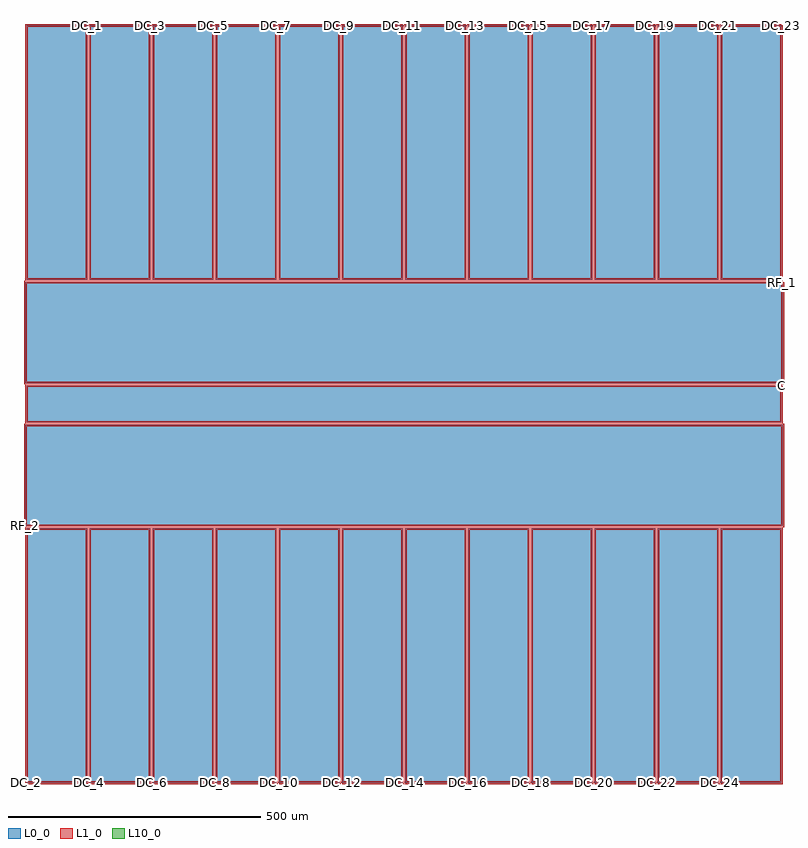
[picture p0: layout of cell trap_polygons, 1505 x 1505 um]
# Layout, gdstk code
import gdstk
lib = gdstk.Library(unit=1e-6, precision=1e-09)
def P(c, l, *ps):  # polygons
    for p in ps: c.add(gdstk.Polygon(p, *l))
L0_0 = (0, 0)
L1_0 = (1, 0)
L10_0 = (10, 0)

trap_polygons = lib.new_cell('trap_polygons')
P(trap_polygons, L0_0, [(627.5,-750),(627.5,-246.5),(747.5,-246.5),(747.5,-750),(627.5,-750)],
  [(747.5,750),(747.5,246.5),(627.5,246.5),(627.5,750),(747.5,750)],
  [(502.5,-750),(502.5,-246.5),(622.5,-246.5),(622.5,-750),(502.5,-750)],
  [(622.5,750),(622.5,246.5),(502.5,246.5),(502.5,750),(622.5,750)],
  [(377.5,-750),(377.5,-246.5),(497.5,-246.5),(497.5,-750),(377.5,-750)],
  [(497.5,750),(497.5,246.5),(377.5,246.5),(377.5,750),(497.5,750)],
  [(252.5,-750),(252.5,-246.5),(372.5,-246.5),(372.5,-750),(252.5,-750)],
  [(372.5,750),(372.5,246.5),(252.5,246.5),(252.5,750),(372.5,750)],
  [(127.5,-750),(127.5,-246.5),(247.5,-246.5),(247.5,-750),(127.5,-750)],
  [(247.5,750),(247.5,246.5),(127.5,246.5),(127.5,750),(247.5,750)],
  [(2.5,-750),(2.5,-246.5),(122.5,-246.5),(122.5,-750),(2.5,-750)],
  [(122.5,750),(122.5,246.5),(2.5,246.5),(2.5,750),(122.5,750)],
  [(-122.5,-750),(-122.5,-246.5),(-2.5,-246.5),(-2.5,-750),(-122.5,-750)],
  [(-2.5,750),(-2.5,246.5),(-122.5,246.5),(-122.5,750),(-2.5,750)],
  [(-247.5,-750),(-247.5,-246.5),(-127.5,-246.5),(-127.5,-750),(-247.5,-750)],
  [(-127.5,750),(-127.5,246.5),(-247.5,246.5),(-247.5,750),(-127.5,750)],
  [(-372.5,-750),(-372.5,-246.5),(-252.5,-246.5),(-252.5,-750),(-372.5,-750)],
  [(-252.5,750),(-252.5,246.5),(-372.5,246.5),(-372.5,750),(-252.5,750)],
  [(-497.5,-750),(-497.5,-246.5),(-377.5,-246.5),(-377.5,-750),(-497.5,-750)],
  [(-377.5,750),(-377.5,246.5),(-497.5,246.5),(-497.5,750),(-377.5,750)],
  [(-622.5,-750),(-622.5,-246.5),(-502.5,-246.5),(-502.5,-750),(-622.5,-750)],
  [(-502.5,750),(-502.5,246.5),(-622.5,246.5),(-622.5,750),(-502.5,750)],
  [(-747.5,-750),(-747.5,-246.5),(-627.5,-246.5),(-627.5,-750),(-747.5,-750)],
  [(-627.5,750),(-627.5,246.5),(-747.5,246.5),(-747.5,750),(-627.5,750)],
  [(747.5,36.5),(747.5,-36.5),(-747.5,-36.5),(-747.5,36.5),(747.5,36.5)],
  [(-750,-241.5),(-750,-41.5),(750,-41.5),(750,-241.5),(-750,-241.5)],
  [(750,241.5),(750,41.5),(-750,41.5),(-750,241.5),(750,241.5)])
P(trap_polygons, L1_0, [(625,-750),(630,-750),(630,-249),(745,-249),(745,-747.5),(627.5,-747.5),(627.5,-752.5),(750,-752.5),(750,-244),(625,-244)],
  [(750,750),(745,750),(745,249),(630,249),(630,747.5),(747.5,747.5),(747.5,752.5),(625,752.5),(625,244),(750,244)],
  [(500,-750),(505,-750),(505,-249),(620,-249),(620,-747.5),(502.5,-747.5),(502.5,-752.5),(625,-752.5),(625,-244),(500,-244)],
  [(625,750),(620,750),(620,249),(505,249),(505,747.5),(622.5,747.5),(622.5,752.5),(500,752.5),(500,244),(625,244)],
  [(375,-750),(380,-750),(380,-249),(495,-249),(495,-747.5),(377.5,-747.5),(377.5,-752.5),(500,-752.5),(500,-244),(375,-244)],
  [(500,750),(495,750),(495,249),(380,249),(380,747.5),(497.5,747.5),(497.5,752.5),(375,752.5),(375,244),(500,244)],
  [(250,-750),(255,-750),(255,-249),(370,-249),(370,-747.5),(252.5,-747.5),(252.5,-752.5),(375,-752.5),(375,-244),(250,-244)],
  [(375,750),(370,750),(370,249),(255,249),(255,747.5),(372.5,747.5),(372.5,752.5),(250,752.5),(250,244),(375,244)],
  [(125,-750),(130,-750),(130,-249),(245,-249),(245,-747.5),(127.5,-747.5),(127.5,-752.5),(250,-752.5),(250,-244),(125,-244)],
  [(250,750),(245,750),(245,249),(130,249),(130,747.5),(247.5,747.5),(247.5,752.5),(125,752.5),(125,244),(250,244)],
  [(0,-750),(5,-750),(5,-249),(120,-249),(120,-747.5),(2.5,-747.5),(2.5,-752.5),(125,-752.5),(125,-244),(0,-244)],
  [(125,750),(120,750),(120,249),(5,249),(5,747.5),(122.5,747.5),(122.5,752.5),(0,752.5),(0,244),(125,244)],
  [(-125,-750),(-120,-750),(-120,-249),(-5,-249),(-5,-747.5),(-122.5,-747.5),(-122.5,-752.5),(0,-752.5),(0,-244),(-125,-244)],
  [(0,750),(-5,750),(-5,249),(-120,249),(-120,747.5),(-2.5,747.5),(-2.5,752.5),(-125,752.5),(-125,244),(0,244)],
  [(-250,-750),(-245,-750),(-245,-249),(-130,-249),(-130,-747.5),(-247.5,-747.5),(-247.5,-752.5),(-125,-752.5),(-125,-244),(-250,-244)],
  [(-125,750),(-130,750),(-130,249),(-245,249),(-245,747.5),(-127.5,747.5),(-127.5,752.5),(-250,752.5),(-250,244),(-125,244)],
  [(-375,-750),(-370,-750),(-370,-249),(-255,-249),(-255,-747.5),(-372.5,-747.5),(-372.5,-752.5),(-250,-752.5),(-250,-244),(-375,-244)],
  [(-250,750),(-255,750),(-255,249),(-370,249),(-370,747.5),(-252.5,747.5),(-252.5,752.5),(-375,752.5),(-375,244),(-250,244)],
  [(-500,-750),(-495,-750),(-495,-249),(-380,-249),(-380,-747.5),(-497.5,-747.5),(-497.5,-752.5),(-375,-752.5),(-375,-244),(-500,-244)],
  [(-375,750),(-380,750),(-380,249),(-495,249),(-495,747.5),(-377.5,747.5),(-377.5,752.5),(-500,752.5),(-500,244),(-375,244)],
  [(-625,-750),(-620,-750),(-620,-249),(-505,-249),(-505,-747.5),(-622.5,-747.5),(-622.5,-752.5),(-500,-752.5),(-500,-244),(-625,-244)],
  [(-500,750),(-505,750),(-505,249),(-620,249),(-620,747.5),(-502.5,747.5),(-502.5,752.5),(-625,752.5),(-625,244),(-500,244)],
  [(-750,-750),(-745,-750),(-745,-249),(-630,-249),(-630,-747.5),(-747.5,-747.5),(-747.5,-752.5),(-625,-752.5),(-625,-244),(-750,-244)],
  [(-625,750),(-630,750),(-630,249),(-745,249),(-745,747.5),(-627.5,747.5),(-627.5,752.5),(-750,752.5),(-750,244),(-625,244)],
  [(750,36.5),(745,36.5),(745,-34),(-745,-34),(-745,34),(747.5,34),(747.5,39),(-750,39),(-750,-39),(750,-39)],
  [(-752.5,-241.5),(-747.5,-241.5),(-747.5,-44),(747.5,-44),(747.5,-239),(-750,-239),(-750,-244),(752.5,-244),(752.5,-39),(-752.5,-39)],
  [(752.5,241.5),(747.5,241.5),(747.5,44),(-747.5,44),(-747.5,239),(750,239),(750,244),(-752.5,244),(-752.5,39),(752.5,39)])
P(trap_polygons, L10_0, [(0,0),(0,0),(0,0),(0,0)])
trap_polygons.add(gdstk.Label('DC_24', (627.5,-750), layer=2, texttype=0))
trap_polygons.add(gdstk.Label('DC_23', (747.5,750), layer=2, texttype=0))
trap_polygons.add(gdstk.Label('DC_22', (502.5,-750), layer=2, texttype=0))
trap_polygons.add(gdstk.Label('DC_21', (622.5,750), layer=2, texttype=0))
trap_polygons.add(gdstk.Label('DC_20', (377.5,-750), layer=2, texttype=0))
trap_polygons.add(gdstk.Label('DC_19', (497.5,750), layer=2, texttype=0))
trap_polygons.add(gdstk.Label('DC_18', (252.5,-750), layer=2, texttype=0))
trap_polygons.add(gdstk.Label('DC_17', (372.5,750), layer=2, texttype=0))
trap_polygons.add(gdstk.Label('DC_16', (127.5,-750), layer=2, texttype=0))
trap_polygons.add(gdstk.Label('DC_15', (247.5,750), layer=2, texttype=0))
trap_polygons.add(gdstk.Label('DC_14', (2.5,-750), layer=2, texttype=0))
trap_polygons.add(gdstk.Label('DC_13', (122.5,750), layer=2, texttype=0))
trap_polygons.add(gdstk.Label('DC_12', (-122.5,-750), layer=2, texttype=0))
trap_polygons.add(gdstk.Label('DC_11', (-2.5,750), layer=2, texttype=0))
trap_polygons.add(gdstk.Label('DC_10', (-247.5,-750), layer=2, texttype=0))
trap_polygons.add(gdstk.Label('DC_9', (-127.5,750), layer=2, texttype=0))
trap_polygons.add(gdstk.Label('DC_8', (-372.5,-750), layer=2, texttype=0))
trap_polygons.add(gdstk.Label('DC_7', (-252.5,750), layer=2, texttype=0))
trap_polygons.add(gdstk.Label('DC_6', (-497.5,-750), layer=2, texttype=0))
trap_polygons.add(gdstk.Label('DC_5', (-377.5,750), layer=2, texttype=0))
trap_polygons.add(gdstk.Label('DC_4', (-622.5,-750), layer=2, texttype=0))
trap_polygons.add(gdstk.Label('DC_3', (-502.5,750), layer=2, texttype=0))
trap_polygons.add(gdstk.Label('DC_2', (-747.5,-750), layer=2, texttype=0))
trap_polygons.add(gdstk.Label('DC_1', (-627.5,750), layer=2, texttype=0))
trap_polygons.add(gdstk.Label('C', (747.5,36.5), layer=2, texttype=0))
trap_polygons.add(gdstk.Label('RF_2', (-750,-241.5), layer=2, texttype=0))
trap_polygons.add(gdstk.Label('RF_1', (750,241.5), layer=2, texttype=0))

lib.write_gds('trap_polygons.gds')
